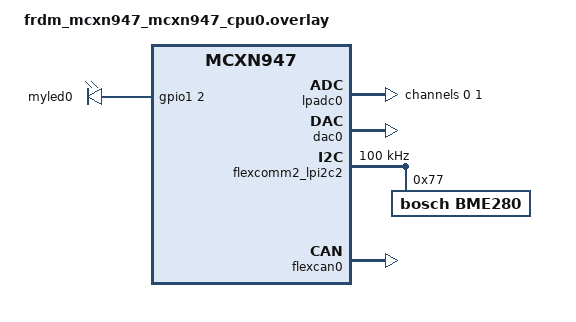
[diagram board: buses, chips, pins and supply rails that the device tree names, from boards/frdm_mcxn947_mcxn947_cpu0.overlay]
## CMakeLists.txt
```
# SPDX-License-Identifier: Apache-2.0

cmake_minimum_required(VERSION 3.20.0)

list(APPEND BOARD_ROOT ${CMAKE_CURRENT_SOURCE_DIR})
set(BOARD "frdm_mcxn947/mcxn947/cpu0")

set(VERSION_MAJOR "1")
set(VERSION_MINOR "0")
set(PATCHLEVEL "0")
set(VERSION_TWEAK "0")
set(EXTRAVERSION "00000000")

find_package(Git QUIET REQUIRED)

execute_process(
    COMMAND "${GIT_EXECUTABLE}" rev-parse --short HEAD
    WORKING_DIRECTORY "${CMAKE_SOURCE_DIR}"
    RESULT_VARIABLE res
    OUTPUT_VARIABLE EXTRAVERSION
    ERROR_QUIET
    OUTPUT_STRIP_TRAILING_WHITESPACE)

set_property(GLOBAL APPEND
    PROPERTY CMAKE_CONFIGURE_DEPENDS
    "${CMAKE_SOURCE_DIR}/.git/index")

set(BOARD_FLASH_RUNNER "probe-rs")
set(BOARD_DEBUG_RUNNER "probe-rs")

# utilize settings to autogenerate a header file to adjust the build inside the C code
#
configure_file (
   "${CMAKE_SOURCE_DIR}/src/VERSION.in"
   "${CMAKE_SOURCE_DIR}/VERSION"
   )

find_package(Zephyr REQUIRED HINTS $ENV{ZEPHYR_BASE})

project(oresat_template LANGUAGES C)

include_directories("${PROJECT_SOURCE_DIR}") # needed so c code can find this header

# (*) zephyr_include_directories(od)
zephyr_include_directories(objdict)

# (*)=disabled until oresat-configs supports code generation for Zephyr's canopennode
# (*) execute_process(COMMAND bash -c "oresat-configs canopennode od.yaml ../../common/od.yaml -d gen")

target_sources(app PRIVATE
  src/main.c
)

# Compile in various demos depending on Kconfig values.
target_sources_ifdef(CONFIG_BLINK_DEMO      app PRIVATE src/blink.c)
target_sources_ifdef(CONFIG_I2C_SENSOR_DEMO app PRIVATE src/i2c_sensor.c)
target_sources_ifdef(CONFIG_DAC_DEMO        app PRIVATE src/dac.c)
target_sources_ifdef(CONFIG_ADC_DEMO        app PRIVATE src/adc.c)
target_sources_ifdef(CONFIG_CAN_DEMO        app PRIVATE src/can.c)
target_sources_ifdef(CONFIG_GPIO_DEMO       app PRIVATE src/gpio.c)
target_sources_ifdef(CONFIG_CAN_DEMO        app PRIVATE objdict/CO_OD.c)
# (*) target_sources_ifdef(CONFIG_CAN_DEMO       app PRIVATE od/CO_OD.c)
```

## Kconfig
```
# SPDX-License-Identifier: Apache-2.0

menu "Zephyr"
source "Kconfig.zephyr"
endmenu

module = APP_TEMPLATE
module-str = APP TEMPLATE

config BOARD_OVERLAY_PRESENT
	bool
	default $(dt_nodelabel_exists,oresat_demo)

if BOARD_OVERLAY_PRESENT

	menu "Oresat demo options"

	config BLINK_DEMO
		bool "Blink an LED"
		default y
		help
		  Enable the thread which blinks an LED.

	config I2C_SENSOR_DEMO
		bool "Enable monitoring an I2C sensor"
		default y
		select I2C
		select SENSOR
		select SENSOR_ASYNC_API
		help
		  Enable reading from a Bosch Sensortec BME280.

	config DAC_DEMO
		bool "Enable generation of a sawtooth pattern."
		default y
		select DAC
		help
		  Enable a slowly repeating sawtooth from 0 to 3.3v.

	config CAN_DEMO
		bool "Enable sending CAN packets."
		default y
		select CAN
		select CANOPENNODE
		select USE_STM32_HAL_FLASH if SOC_STM32F091XC
		select USE_STM32_HAL_FLASH_EX if SOC_STM32F091XC
		select USE_STM32_HAL_CAN if SOC_STM32F091XC
		help
		  Enable CAN interface and send data from CO_OD.

	config GPIO_DEMO
		bool "Enable monitoring GPIOs."
		default y
		help
		  Enable logging of initial GPIO states, followed
		  by periodic logging of changes.

	config ADC_DEMO
		bool "Enable monitoring one or more ADC channels."
		default y
		select ADC
		select DMA
		select ADC_STM32 if SOC_STM32F091XC
		select ADC_STM32_DMA if SOC_STM32F091XC
		select DMA_STM32 if SOC_STM32F091XC
		help
		  Outputs the data scaled to mV.

	if ADC_DEMO

		config SEQUENCE_SAMPLES
			int "Number of samples to be made on the sequence for each channel."
			default 5

		config SEQUENCE_RESOLUTION
			int "Set the resolution of the sequence readings."
			default 12

		config SEQUENCE_32BITS_REGISTERS
			bool "ADC data sequences are on 32bits"
			default n

	endif  # ADC_DEMO

	if CAN_DEMO && !SOC_STM32F091XC && !ARCH_POSIX

		config MCUBOOT_ALLOWED
			bool "MCUboot allowed."
			default y
			select BOOTLOADER_MCUBOOT
			select MCUBOOT_GENERATE_UNSIGNED_IMAGE
			select FLASH
			select FLASH_MAP
			select STREAM_FLASH
			select IMG_MANAGER
			select MCUBOOT_GENERATE_CONFIRMED_IMAGE
			select CANOPENNODE_PROGRAM_DOWNLOAD
			help
			  Define helper symbol CONFIG_MCUBOOT_ALLOWED for all supported
			  architectures that have room for the required partitions in flash
			  and have those partitions defined in the device tree. This
			  eliminates the need for the user to either change prj.conf to
			  enable MCUBOOT or provide an EXTRA_CONF_FILE option to west that
			  names an overlay file.

	endif

	endmenu

endif # BOARD_OVERLAY_PRESENT
```

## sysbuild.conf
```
SB_CONFIG_BOOTLOADER_MCUBOOT=n
SB_CONFIG_BOOT_SIGNATURE_TYPE_NONE=y
```

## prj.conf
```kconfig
CONFIG_PRINTK=y
CONFIG_CONSOLE=y
CONFIG_SERIAL=y
CONFIG_UART_CONSOLE=y

CONFIG_PM=y
CONFIG_PM_DEVICE=y
CONFIG_PM_DEVICE_RUNTIME=y
CONFIG_PM_POLICY_CUSTOM=y
#CONFIG_PM_S2RAM=y

CONFIG_TICKLESS_KERNEL=y

CONFIG_COUNTER=y
CONFIG_COUNTER_MCUX_LPTMR_ALARM=y
CONFIG_PM_PREWAKEUP_CONV_MODE_CEIL=y

CONFIG_PM_DEVICE_SYSTEM_MANAGED=y
```

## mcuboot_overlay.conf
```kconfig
CONFIG_BOOTLOADER_MCUBOOT=y
CONFIG_MCUBOOT_GENERATE_UNSIGNED_IMAGE=y
# CONFIG_MCUBOOT_SIGNATURE_KEY_FILE=""
CONFIG_FLASH=y
CONFIG_FLASH_MAP=y
CONFIG_STREAM_FLASH=y
CONFIG_IMG_MANAGER=y
CONFIG_MCUBOOT_IMG_MANAGER=y
CONFIG_MCUBOOT_GENERATE_CONFIRMED_IMAGE=n
```

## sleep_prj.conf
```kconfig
CONFIG_PRINTK=y
CONFIG_CONSOLE=y
CONFIG_SERIAL=y
CONFIG_UART_CONSOLE=y

CONFIG_PM=y
CONFIG_PM_DEVICE=y
CONFIG_PM_DEVICE_RUNTIME=y

CONFIG_TICKLESS_KERNEL=y
```

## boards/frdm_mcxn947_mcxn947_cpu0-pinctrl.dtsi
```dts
&pinctrl {
	pinmux_flexcomm2_lpi2c: pinmux_flexcomm2_lpi2c {
		group0 {
			pinmux = <FC2_P0_PIO4_0>, // SDA  Header: J7  Pin: 8
    			     <FC2_P1_PIO4_1>; // SCL  Header: J7  Pin: 6
			slew-rate = "fast";
			drive-strength = "low";
			input-enable;
			bias-pull-up;
			drive-open-drain;
		};
	};

    pinmux_dac0: pinmux_dac0 {
        group0 {
            pinmux = <DAC0_OUT_PIO4_2>; // Header: J1  Pin: 4
            drive-strength = "low";
            slew-rate = "fast";
        };
    };

    pinmux_lpadc0: pinmux_lpadc0 {
        group0 {
            pinmux = <ADC0_A14_PIO0_22>, // Header: J4  Pin: 8
                     <ADC0_A15_PIO0_23>; // Header: J4  Pin: 12
            slew-rate = "fast";
            drive-strength = "low";
        };
    };

    pinmux_flexcan0: pinmux_flexcan0 {
        group0 {
            pinmux = <CAN0_TXD_PIO1_10>,
                     <CAN0_RXD_PIO1_11>;
            slew-rate = "fast";
            drive-strength = "low";
        };
    };
};
```

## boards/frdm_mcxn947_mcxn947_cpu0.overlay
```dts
#include <zephyr/dt-bindings/adc/adc.h>
#include <zephyr/dt-bindings/adc/mcux-lpadc.h>

#include "frdm_mcxn947_mcxn947_cpu0-pinctrl.dtsi"

/ {
	oresat_demo: oresat-demo-enabled {}; // Enable demos for supported boards

	zephyr,user {
		dac = <&dac0>;
		dac_channel_id = <0>;
		dac_resolution = <12>;
	};

	aliases {
		dac0 = &dac0;
		adc0 = &lpadc0;
		i2c0 = &flexcomm2_lpi2c2;
		led0 = &myled0;
		can0 = &flexcan0;
	};

	leds {
		compatible = "gpio-leds";
		myled0: led_0 {
			gpios = <&gpio1 2 GPIO_ACTIVE_HIGH>;
		};
	};
};

&lpadc0 {
	#address-cells = <1>;
	#size-cells = <0>;
	voltage-ref = <0x0>; // Use 3.3V reference
	pinctrl-0 = <&pinmux_lpadc0>;
	pinctrl-names = "default";

	lpadc0_0: channel@0 {
		reg = <0>;
		zephyr,gain = "ADC_GAIN_1";
		zephyr,reference = "ADC_REF_EXTERNAL0";
		zephyr,vref-mv = <3300>;
		zephyr,acquisition-time = <ADC_ACQ_TIME(ADC_ACQ_TIME_MICROSECONDS,2)>;
		zephyr,resolution = <12>;
		zephyr,oversampling = <5>;
		zephyr,input-positive = <MCUX_LPADC_CH14A>;
		/delete-property/ zephyr,differential;
	};
	lpadc0_1: channel@1 {
		reg = <1>;
		zephyr,gain = "ADC_GAIN_1";
		zephyr,reference = "ADC_REF_EXTERNAL0";
		zephyr,vref-mv = <3300>;
		zephyr,acquisition-time = <ADC_ACQ_TIME(ADC_ACQ_TIME_MICROSECONDS,2)>;
		zephyr,resolution = <12>;
		zephyr,oversampling = <5>;
		zephyr,input-positive = <MCUX_LPADC_CH15A>;
		/delete-property/ zephyr,differential;
	};
};

&dac0 {
	status = "okay";
	pinctrl-0 = <&pinmux_dac0>;
	pinctrl-names = "default";
};

&flexcomm2_lpi2c2 {
	status = "okay";
	pinctrl-0 = <&pinmux_flexcomm2_lpi2c>;
	pinctrl-names = "default";
	clock-frequency = <I2C_BITRATE_STANDARD>;

	bme280: bme280@77 {
		compatible = "bosch,bme280";
		reg = <0x77>;
		status = "okay";
	};
};

&flexcan0 {
	status = "okay";
	pinctrl-0 = <&pinmux_flexcan0>;
	pinctrl-names = "default";
};
```

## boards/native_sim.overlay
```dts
#include <zephyr/dt-bindings/adc/adc.h>

/ {
    oresat_demo: oresat-demo-enabled {}; // Enable demos for supported boards

    chosen {
        zephyr,canbus = &can0;
    };

    aliases {
        adc0 = &adc;
        /* can0 = &can; */
    };

    adc: adc {
        compatible = "zephyr,adc-emul";
        status = "okay";
        #address-cells = <1>;
        #size-cells = <0>;
        nchannels = <32>;
        ref-internal-mv = <1>;

        channel@0 {
            reg = <0>;
            zephyr,gain = "ADC_GAIN_1";
            zephyr,reference = "ADC_REF_INTERNAL";
            zephyr,vref-mv = <3300>;
            zephyr,acquisition-time = <ADC_ACQ_TIME(ADC_ACQ_TIME_MICROSECONDS,2)>;
            zephyr,resolution = <12>;
            zephyr,oversampling = <5>;
            zephyr,input-positive = <0>;
        };
    };

    can: can {
        compatible = "zephyr,native-linux-can";
        status = "okay";
        host-interface = "zcan0";
        bitrate = <1000>;
    };
};
```

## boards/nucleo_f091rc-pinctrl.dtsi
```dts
&pinctrl {
    i2c1_sda_pb9: i2c1_sda_pb9 {
        pinmux = <STM32_PINMUX('B', 9, AF1)>; // SDA  Arduino: D14  Pin: PB9
        slew-rate = "medium-speed";
        bias-pull-up;
        drive-open-drain;
    };

    i2c1_scl_pb8: i2c1_scl_pb8 {
        pinmux = <STM32_PINMUX('B', 8, AF1)>; // SCL  Arduino: D15  Pin: PB8
        slew-rate = "medium-speed";
        bias-pull-up;
        drive-open-drain;
    };

    dac1_out1_pa4: dac1_out1_pa4 {
        pinmux = <STM32_PINMUX('A', 4, ANALOG)>; // DAC_OUT1  Arduino: A2  Pin: PA4
    };

    adc1_in0_pa0: adc1_in0_pa0 {
        pinmux = <STM32_PINMUX('A', 0, ANALOG)>; // ADC1_IN0  Arduino: A0  Pin: PA0
    };

    adc1_in1_pa1: adc1_in1_pa1 {
        pinmux = <STM32_PINMUX('A', 1, ANALOG)>; // ADC1_IN1  Arduino: A1  Pin: PA1
    };
};
```

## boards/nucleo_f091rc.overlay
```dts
#include <zephyr/dt-bindings/adc/adc.h>
#include <zephyr/dt-bindings/pinctrl/stm32-pinctrl.h>
#include <zephyr/dt-bindings/dma/stm32_dma.h>

#include "nucleo_f091rc-pinctrl.dtsi"

/ {
	oresat_demo: oresat-demo-enabled {}; // Enable demos for supported boards

	zephyr,user {
		dac = <&dac1>;
		dac_channel_id = <1>;
		dac_resolution = <12>;
	};

	aliases {
		dac0 = &dac1;
		adc0 = &adc1;
		i2c0 = &i2c1;
		led0 = &myled0;
	};

	leds {
		compatible = "gpio-leds";
		myled0: led_0 {
			gpios = <&gpioa 5 GPIO_ACTIVE_HIGH>;
		};
	};
};

&dma1 {
	status = "okay";
};

&adc1 {
	#address-cells = <1>;
	#size-cells = <0>;
	pinctrl-0 = <&adc1_in0_pa0 &adc1_in1_pa1>;
	pinctrl-names = "default";
	dmas = <&dma1 1 (STM32_DMA_PERIPH_RX |
					STM32_DMA_PRIORITY_HIGH |
					STM32_DMA_PERIPH_16BITS |
					STM32_DMA_MEM_16BITS)>;
	dma-names = "rx";

	adc1_0: channel@0 {
		reg = <0>;
		zephyr,gain = "ADC_GAIN_1";
		zephyr,reference = "ADC_REF_INTERNAL";
		zephyr,vref-mv = <3300>;
		zephyr,acquisition-time = <ADC_ACQ_TIME(ADC_ACQ_TIME_TICKS, 240)>;
		zephyr,resolution = <12>;
		zephyr,oversampling = <5>;
		/delete-property/ zephyr,differential;
	};
	adc1_1: channel@1 {
		reg = <1>;
		zephyr,gain = "ADC_GAIN_1";
		zephyr,reference = "ADC_REF_INTERNAL";
		zephyr,vref-mv = <3300>;
		zephyr,acquisition-time = <ADC_ACQ_TIME(ADC_ACQ_TIME_TICKS, 240)>;
		zephyr,resolution = <12>;
		zephyr,oversampling = <5>;
		/delete-property/ zephyr,differential;
	};
};

&dac1 {
	status = "okay";
	pinctrl-0 = <&dac1_out1_pa4>;
	pinctrl-names = "default";
};

&i2c1 {
	status = "okay";
	pinctrl-0 = <&i2c1_scl_pb8 &i2c1_sda_pb9>;
	pinctrl-names = "default";
	clock-frequency = <I2C_BITRATE_STANDARD>;

	bme280: bme280@77 {
		compatible = "bosch,bme280";
		reg = <0x77>;
		status = "okay";
	};
};
```

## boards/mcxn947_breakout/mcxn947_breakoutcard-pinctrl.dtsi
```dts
/*
 * Copyright 2024 NXP
 * SPDX-License-Identifier: Apache-2.0
 */

#include <nxp/mcx/MCXN947VNL-pinctrl.h>

&pinctrl {
	pinmux_flexcomm0_lpi2c: pinmux_flexcomm0_lpi2c {
		group0 {
			pinmux = <FC0_P0_PIO0_16>,
				<FC0_P1_PIO0_17>;
			slew-rate = "fast";
			drive-strength = "low";
			input-enable;
			bias-pull-up;
			drive-open-drain;
		};
	};

	pinmux_flexcomm3_lpspi: pinmux_flexcomm3_lpspi {
		group0 {
			pinmux = <FC3_P0_PIO1_0>,
				<FC3_P1_PIO1_1>,
				<FC3_P2_PIO1_2>,
				<FC3_P3_PIO1_3>;
			slew-rate = "fast";
			drive-strength = "low";
			input-enable;
		};
	};

	pinmux_flexcomm2_lpi2c: pinmux_flexcomm2_lpi2c {
		group0 {
			pinmux = <FC2_P0_PIO4_0>,
				<FC2_P1_PIO4_1>;
			slew-rate = "fast";
			drive-strength = "low";
			input-enable;
			bias-pull-up;
			drive-open-drain;
		};
	};

	pinmux_flexcomm2_lpuart: pinmux_flexcomm2_lpuart {
		group0 {
			pinmux = <FC2_P2_PIO4_2>,
				<FC2_P3_PIO4_3>;
			slew-rate = "fast";
			drive-strength = "low";
			input-enable;
		};
	};

	pinmux_flexcomm4_lpuart: pinmux_flexcomm4_lpuart {
		group0 {
			pinmux = <FC4_P0_PIO1_8>,
				<FC4_P1_PIO1_9>;
			slew-rate = "fast";
			drive-strength = "low";
			input-enable;
		};
	};

	pinmux_flexspi: pinmux_flexspi {
		group0 {
			pinmux = <FLEXSPI0_A_SS0_b_PIO3_0>,
					<FLEXSPI0_A_SCLK_PIO3_7>,
					<FLEXSPI0_A_DQS_PIO3_6>,
					<FLEXSPI0_A_DATA0_PIO3_8>,
					<FLEXSPI0_A_DATA1_PIO3_9>;
			input-enable;
			slew-rate = "fast";
			drive-strength = "low";
		};
		group1 {
			pinmux = <FLEXSPI0_A_DATA2_PIO3_10>,
					<FLEXSPI0_A_DATA3_PIO3_11>;
			input-enable;
			slew-rate = "fast";
			drive-strength = "low";
			bias-pull-up;
		};
	};

	pinmux_dac0: pinmux_dac0 {
		group0 {
			pinmux = <DAC0_OUT_PIO4_2>;
			drive-strength = "low";
			slew-rate = "fast";
		};
	};

	pinmux_flexpwm1_pwm0: pinmux_flexpwm1_pwm0 {
		group0 {
			pinmux = <PWM1_A0_PIO2_6>,
				<PWM1_B0_PIO2_7>;
			slew-rate = "fast";
			drive-strength = "low";
		};
	};

	pinmux_flexpwm1_pwm1: pinmux_flexpwm1_pwm1 {
		group0 {
			pinmux = <PWM1_A1_PIO2_4>,
				<PWM1_B1_PIO2_5>;
			slew-rate = "fast";
			drive-strength = "low";
		};
	};

	pinmux_flexpwm1_pwm2: pinmux_flexpwm1_pwm2 {
		group0 {
			pinmux = <PWM1_A2_PIO2_2>,
				<PWM1_B2_PIO2_3>;
			slew-rate = "fast";
			drive-strength = "low";
		};
	};

	pinmux_usdhc0: pinmux_usdhc0 {
		group0 {
			pinmux = <SDHC0_CMD_PIO2_5>,
				   <SDHC0_D0_PIO2_3>,
				   <SDHC0_D1_PIO2_2>,
				   <SDHC0_D2_PIO2_7>,
				   <SDHC0_D3_PIO2_6>;
			slew-rate = "fast";
			drive-strength = "low";
			bias-pull-up;
			input-enable;
		};
		group1 {
			pinmux = <SDHC0_CLK_PIO2_4>;
			slew-rate = "fast";
			drive-strength = "low";
			input-enable;
		};
	};

	pinmux_lpadc0: pinmux_lpadc0 {
		group0 {
			pinmux = <ADC0_A1_PIO4_15>,
					 <ADC0_A2_PIO4_23>;
			slew-rate = "fast";
			drive-strength = "low";
		};
	};

	pinmux_lpcmp0: pinmux_lpcmp0 {
		group0 {
			pinmux = <CMP0_IN0_PIO1_0>;
			drive-strength = "low";
			slew-rate = "fast";
			bias-pull-up;
		};
	};

	pinmux_flexcan0: pinmux_flexcan0 {
		group0 {
			pinmux = <CAN0_TXD_PIO1_10>,
				<CAN0_RXD_PIO1_11>;
			slew-rate = "fast";
			drive-strength = "low";
			input-enable;
		};
	};

	pinmux_sctimer: pinmux_sctimer {
		group0 {
			pinmux = <SCT0_OUT0_PIO2_2>;
			slew-rate = "fast";
			drive-strength = "low";
			input-enable;
		};
	};
};
```

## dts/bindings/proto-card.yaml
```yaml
# Oresat proto card

description: Oresat proto card

compatible: "proto-card"

properties:
  tp84-p0-3-gpios:
    type: phandle-array
    required: true
    description: GPIO input or output.

  tp84-p0-3-gpios:
    type: phandle-array
    required: true
    description: GPIO input or output.

  tp85-p0-4-gpios:
    type: phandle-array
    required: true
    description: GPIO input or output.

  tp86-p0-5-gpios:
    type: phandle-array
    required: true
    description: GPIO input or output.

  tp78-p0-18-gpios:
    type: phandle-array
    required: true
    description: GPIO input or output.

  tp79-p0-19-gpios:
    type: phandle-array
    required: true
    description: GPIO input or output.

  tp80-p0-20-gpios:
    type: phandle-array
    required: true
    description: GPIO input or output.

  tp81-p0-21-gpios:
    type: phandle-array
    required: true
    description: GPIO input or output.

  tp82-p0-22-gpios:
    type: phandle-array
    required: true
    description: GPIO input or output.

  tp83-p0-23-gpios:
    type: phandle-array
    required: true
    description: GPIO input or output.

  tp68-p1-0-gpios:
    type: phandle-array
    required: true
    description: GPIO input or output.

  tp69-p1-1-gpios:
    type: phandle-array
    required: true
    description: GPIO input or output.

  tp70-p1-2-gpios:
    type: phandle-array
    required: true
    description: GPIO input or output.

  tp71-p1-3-gpios:
    type: phandle-array
    required: true
    description: GPIO input or output.

  tp72-p1-4-gpios:
    type: phandle-array
    required: true
    description: GPIO input or output.

  tp73-p1-5-gpios:
    type: phandle-array
    required: true
    description: GPIO input or output.

  tp74-p1-6-gpios:
    type: phandle-array
    required: true
    description: GPIO input or output.

  tp75-p1-7-gpios:
    type: phandle-array
    required: true
    description: GPIO input or output.

  tp5-p1-12-gpios:
    type: phandle-array
    required: true
    description: GPIO input or output.

  tp7-p1-14-gpios:
    type: phandle-array
    required: true
    description: GPIO input or output.

  tp8-p1-15-gpios:
    type: phandle-array
    required: true
    description: GPIO input or output.

  tp9-p2-0-gpios:
    type: phandle-array
    required: true
    description: GPIO input or output.

  tp10-p2-1-gpios:
    type: phandle-array
    required: true
    description: GPIO input or output.

  tp52-p3-1-gpios:
    type: phandle-array
    required: true
    description: GPIO input or output.

  tp60-p3-12-gpios:
    type: phandle-array
    required: true
    description: GPIO input or output.

  tp59-p3-13-gpios:
    type: phandle-array
    required: true
    description: GPIO input or output.

  tp58-p3-14-gpios:
    type: phandle-array
    required: true
    description: GPIO input or output.

  tp57-p3-15-gpios:
    type: phandle-array
    required: true
    description: GPIO input or output.

  tp56-p3-16-gpios:
    type: phandle-array
    required: true
    description: GPIO input or output.

  tp55-p3-17-gpios:
    type: phandle-array
    required: true
    description: GPIO input or output.

  tp62-p3-20-gpios:
    type: phandle-array
    required: true
    description: GPIO input or output.

  tp63-p3-21-gpios:
    type: phandle-array
    required: true
    description: GPIO input or output.

  tp29-p4-1-gpios:
    type: phandle-array
    required: true
    description: GPIO input or output.

  tp27-p4-3-gpios:
    type: phandle-array
    required: true
    description: GPIO input or output.

  tp26-p4-4-gpios:
    type: phandle-array
    required: true
    description: GPIO input or output.

  tp25-p4-5-gpios:
    type: phandle-array
    required: true
    description: GPIO input or output.

  tp22-p4-6-gpios:
    type: phandle-array
    required: true
    description: GPIO input or output.

  tp20-p4-7-gpios:
    type: phandle-array
    required: true
    description: GPIO input or output.

  tp41-p4-19-gpios:
    type: phandle-array
    required: true
    description: GPIO input or output.

  tp64-p5-0-gpios:
    type: phandle-array
    required: true
    description: GPIO input or output.

  tp65-p5-1-gpios:
    type: phandle-array
    required: true
    description: GPIO input or output.

  tp66-p5-2-gpios:
    type: phandle-array
    required: true
    description: GPIO input or output.

  tp67-p5-3-gpios:
    type: phandle-array
    required: true
    description: GPIO input or output.
```

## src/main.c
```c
#include "zephyr/pm/state.h"
#include <zephyr/kernel.h>
#include <zephyr/sys/printk.h>
#include <zephyr/pm/policy.h>
#include <zephyr/pm/pm.h>

#define SLEEP_TIME_MS 5000

 //This function is called by Zephyr's PM subsystem whenever the CPU becomes idle.
 
 //PM Policy callback
const struct pm_state_info *pm_policy_next_state(uint8_t cpu, int32_t ticks)
{
    ARG_UNUSED(ticks);   //Prevents unused variable warnings 

    printk("\n>>> pm_policy_next_state() CALLED <<<\n");

    const struct pm_state_info *cpu_states;      // Pointer to available PM states
    uint8_t num_states;                          // Number of available states

    num_states = pm_state_cpu_get_all(cpu, &cpu_states);   // Get all supported power states for this CPU

    printk("Number of CPU power states: %d\n", num_states);

    if (num_states == 0) {
        printk("ERROR: No power states found!\n");
        return NULL;   //No state available
    }

// Loop through all available states
    for (int i = 0; i < num_states; i++) {

        printk("Checking state %d (enum value = %d)\n",
               i,
               cpu_states[i].state);

        if (cpu_states[i].state == PM_STATE_SUSPEND_TO_IDLE) {

            printk("Slecting PM_STATE_SUSPEND_TO_IDLE");

            return &cpu_states[i];
        }

        //if (cpu_states[i].state == PM_STATE_RUNTIME_IDLE) {

        //    printk("Selecting PM_STATE_RUNTIME_IDLE\n");

        //    return &cpu_states[i];     //tells zephyr to enter this state
        //}
    }

    printk("ERROR: PM_STATE_RUNTIME_IDLE not found!\n");

    return NULL;   //No matching state found
}

int main(void)
{
    printk("\n");
    printk("=====================================\n");
    printk(" MCXN947 Sleep Mode Test\n");
    printk("=====================================\n");

    printk("\nCPU ACTIVE\n");                   //CPU running normally
    printk("Preparing to enter Sleep...\n");

    k_sleep(K_MSEC(SLEEP_TIME_MS));   // Allows idle mode

    printk("CPU AWAKE\n");    //Runs after sleep completes

    while (1) {
        printk("done sleeping");
    }

    return 0;
}
```

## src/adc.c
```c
/**
 * adc.c
 *
 * Original code came from zephyr/samples/driver/adc_sequence.
 *
 * Modified slightly to run as a thread and use logging.
 */

#ifdef CONFIG_ADC_EMUL
#include <zephyr/drivers/adc/adc_emul.h>
#include <math.h>
#endif /* ifdef CONFIG_ADC_EMUL */

#include <stdio.h>
#include <zephyr/kernel.h>
#include <zephyr/sys/printk.h>
#include <zephyr/sys/__assert.h>

#include <zephyr/device.h>
#include <zephyr/devicetree.h>
#include <zephyr/dsp/print_format.h>
#include <zephyr/drivers/adc.h>
#include <zephyr/logging/log.h>

LOG_MODULE_REGISTER(oresat_adc_demo, LOG_LEVEL_DBG);

/* size of stack area used by each thread */
#define STACKSIZE 1024

/* scheduling priority used by each thread */
#define PRIORITY 7

/* 1000 msec = 1 sec */
#define ADC_SLEEP_TIME_MS 100 /* Use 5 to generate more data to graph samples that follow the DAC output */

/* ADC node from the devicetree. */
#define ADC_NODE DT_ALIAS(adc0)

/* Auxiliary macro to obtain channel vref, if available. */
#define CHANNEL_VREF(node_id) DT_PROP_OR(node_id, zephyr_vref_mv, 0)

/* Data of ADC device specified in devicetree. */
static const struct device *adc = DEVICE_DT_GET(ADC_NODE);

/* Data array of ADC channels for the specified ADC. */
static const struct adc_channel_cfg channel_cfgs[] = {
	DT_FOREACH_CHILD_SEP(ADC_NODE, ADC_CHANNEL_CFG_DT, (,))};

/* Data array of ADC channel voltage references. */
static uint32_t vrefs_mv[] = {DT_FOREACH_CHILD_SEP(ADC_NODE, CHANNEL_VREF, (,))};

/* Get the number of channels defined on the DTS. */
#define CHANNEL_COUNT ARRAY_SIZE(channel_cfgs)

static int handle_adc(void)
{
	int err;
#ifdef CONFIG_SEQUENCE_32BITS_REGISTERS
	uint32_t channel_reading[CONFIG_SEQUENCE_SAMPLES][CHANNEL_COUNT];
#else
	uint16_t channel_reading[CONFIG_SEQUENCE_SAMPLES][CHANNEL_COUNT];
#endif

	/* Options for the sequence sampling. */
	const struct adc_sequence_options options = {
		.extra_samplings = CONFIG_SEQUENCE_SAMPLES - 1,
		.interval_us = 0,
	};

	/* Configure the sampling sequence to be made. */
	struct adc_sequence sequence = {
		.buffer = channel_reading,
		/* buffer size in bytes, not number of samples */
		.buffer_size = sizeof(channel_reading),
		.resolution = CONFIG_SEQUENCE_RESOLUTION,
		.options = &options,
	};

	LOG_INF("Starting ADC demo");

	if (!device_is_ready(adc)) {
		LOG_ERR("ADC controller device %s not ready", adc->name);
		return 0;
	}

	LOG_INF("Channels: %d, sequence samples: %d, resolution: %d",
		   CHANNEL_COUNT, CONFIG_SEQUENCE_SAMPLES, CONFIG_SEQUENCE_RESOLUTION);

	/* Configure channels individually prior to sampling. */
	for (size_t i = 0U; i < CHANNEL_COUNT; i++) {
		sequence.channels |= BIT(channel_cfgs[i].channel_id);
		err = adc_channel_setup(adc, &channel_cfgs[i]);
		if (err < 0) {
			LOG_ERR("Could not setup channel #%d (%d)\n", i, err);
			return 0;
		}
		if ((vrefs_mv[i] == 0) && (channel_cfgs[i].reference == ADC_REF_INTERNAL)) {
			vrefs_mv[i] = adc_ref_internal(adc);
		}
		#ifdef CONFIG_ADC_CONFIGURABLE_INPUTS
		LOG_INF("Channel: %u, vref_mv: %u, gain: %u, acq time: %u, diff: %u, inp_pos: %u, inp_neg: %u",
				channel_cfgs[i].channel_id, vrefs_mv[i], channel_cfgs[i].gain, channel_cfgs[i].acquisition_time,
				channel_cfgs[i].differential, channel_cfgs[i].input_positive, channel_cfgs[i].input_negative);
		#else
		LOG_INF("Channel: %u, vref_mv: %u, gain: %u, acq time: %u, diff: %u",
				channel_cfgs[i].channel_id, vrefs_mv[i], channel_cfgs[i].gain, channel_cfgs[i].acquisition_time,
				channel_cfgs[i].differential);
		#endif
	}

#ifdef CONFIG_ADC_EMUL
	uint32_t adc_val = 0;
#endif /* ifdef CONFIG_ADC_EMUL */

	while (1) {
		k_msleep(ADC_SLEEP_TIME_MS);

#ifdef CONFIG_ADC_EMUL
		uint32_t adc_raw = (uint32_t)((sin(adc_val) + 1) * 1000);
		adc_emul_const_raw_value_set(adc, 0, adc_raw);
		adc_val++;
#endif /* ifdef CONFIG_ADC_EMUL */

		err = adc_read(adc, &sequence);
		if (err < 0) {
			LOG_ERR("Could not read (%d)", err);
			continue;
		}

		for (size_t channel_index = 0U; channel_index < CHANNEL_COUNT; channel_index++) {
			int32_t raw;
			int32_t val_mv;

			printk("Channel %" PRId32 ":", channel_index);

			for (size_t sample_index = 0U; sample_index < CONFIG_SEQUENCE_SAMPLES;
			     sample_index++) {

				raw = channel_reading[sample_index][channel_index];
				val_mv = raw;

				err = adc_raw_to_millivolts(vrefs_mv[channel_index],
							    channel_cfgs[channel_index].gain,
							    CONFIG_SEQUENCE_RESOLUTION, &val_mv);

				/* conversion to mV may not be supported, skip if not */
				if ((err < 0) || vrefs_mv[channel_index] == 0) {
					printk("% 4" PRId32 ",", raw);
				} else {
					printk("% 4" PRId32 ",", val_mv);
				}
			}
			printk("\n");
		}
	}

	return 0;
}

K_THREAD_DEFINE(adc_id, STACKSIZE, handle_adc, NULL, NULL, NULL, PRIORITY, 0, 0);
```

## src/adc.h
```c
#if !defined(_ADC_H_)
#define _ADC_H_

int get_num_adc_channels(void);

int init_adc(void);

int acquire_adc_readings(void);

int read_adc(unsigned int log_adc_num, int32_t *val_mv, uint32_t *val_raw);

#endif
```

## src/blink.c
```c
/**
 * blink.c
 *
 * Code came from https://github.com/Blen-E/pracblink, which
 * originally from zephyr/samples/basic/blinky.
 *
 * Modified slightly to run as a thread and use logging.
 */
#include <stdio.h>
#include <zephyr/kernel.h>
#include <zephyr/drivers/gpio.h>
#include <zephyr/sys/printk.h> 
#include <zephyr/sys/__assert.h>

#include <zephyr/device.h>
#include <zephyr/devicetree.h>
#include <zephyr/logging/log.h>

LOG_MODULE_REGISTER(oresat_blink_demo, LOG_LEVEL_INF);

/* size of stack area used by each thread */
#define STACKSIZE 1024

/* scheduling priority used by each thread */
#define PRIORITY 7

/* 1000 msec = 1 sec */
#define LED_SLEEP_TIME_MS   1000

/* The devicetree node identifier for the "led0" alias. */
#define LED0_NODE DT_ALIAS(led0)

extern const k_tid_t blink_id;

static int handle_blink(void *p1, void *p2, void *p3)
{
	int ret;
	const struct gpio_dt_spec led = GPIO_DT_SPEC_GET(LED0_NODE, gpios);

	k_thread_name_set(blink_id, "blink_thread");
	LOG_INF("Starting blink demo");

	/* Can we use the LED? */
	if (!device_is_ready(led.port)) {
		LOG_ERR("LED device is not ready");
		return -1;
	}

	/* Set it up */
	ret = gpio_pin_configure_dt(&led, GPIO_OUTPUT_ACTIVE);
	if (ret < 0) {
		LOG_ERR("Could not configure the LED GPIO pin: %d", ret);
		return ret;
	}

	/* Thread loop */
	while (1) {
		gpio_pin_toggle_dt(&led);
		LOG_DBG("The light is blinking!");
		k_msleep(LED_SLEEP_TIME_MS);
	}
	return 0;
}

K_THREAD_DEFINE(blink_id, STACKSIZE, handle_blink, NULL, NULL, NULL, PRIORITY, 0, 0);
```

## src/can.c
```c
#include <zephyr/kernel.h>
#include <zephyr/device.h>
#include <zephyr/sys/reboot.h>
#include <zephyr/logging/log.h>
#include <zephyr/sys/printk.h>
#include <zephyr/drivers/gpio.h>
#include <zephyr/dfu/mcuboot.h>
#include <canopennode.h>
#include <CO_OD.h>
#include <board_sensors.h>
#include <oresat.h>

LOG_MODULE_REGISTER(can_thread, LOG_LEVEL_DBG);

#define CAN_INTERFACE (DEVICE_DT_GET(DT_CHOSEN(zephyr_canbus)))
#define CAN_BITRATE (DT_PROP_OR(DT_CHOSEN(zephyr_canbus), bitrate, \
					 DT_PROP_OR(DT_CHOSEN(zephyr_canbus), bus_speed, \
								CONFIG_CAN_DEFAULT_BITRATE) / 1000))

#define CAN_THREAD_STACK_SIZE 2048
#define CAN_THREAD_PRIORITY 0
extern const k_tid_t can_id;

static bool run_self_tests(void)
{
	LOG_INF("Running system self-tests...");

	// Placeholder for board/app-specific checks
	bool tests_passed = true;

	return tests_passed;
}

static void handle_can(void *p1, void *p2, void *p3)
{
	int err;
	uint16_t timeout;
	uint16_t wr_timeout_count;
	uint32_t elapsed = 0U;
	int64_t timestamp;
	CO_NMT_reset_cmd_t reset = CO_RESET_NOT;
	struct canopen_context can = {.dev = CAN_INTERFACE};
	uint8_t node_id = oresat_get_node_id();

	k_thread_name_set(can_id, "can_thread");

	LOG_INF("Starting CAN thread");

	// Confirm a newly booted MCUboot image if self-tests pass
	if (!IS_ENABLED(CONFIG_BOOTLOADER_MCUBOOT)) {
		/* do nothing */
	} else if (!boot_is_img_confirmed()) {
		LOG_INF("New firmware detected. Pending confirmation.");

		if (run_self_tests()) {
			LOG_INF("Self-tests passed. Confirming image.");
			int rc = boot_write_img_confirmed();
			if (rc < 0) {
				LOG_ERR("Failed to confirm MCUboot image: %d", rc);
			}
		} else {
			LOG_ERR("Self-tests failed. Rebooting to revert firmware...");
			k_msleep(500); // Let logs flush
			sys_reboot(SYS_REBOOT_COLD);
		}
	} else {
		LOG_INF("Firmware already confirmed.");
	}

	oresat_fix_pdo_cob_ids(node_id);

	LOG_DBG("Opening CAN device");
	if (!device_is_ready(can.dev)) {
		LOG_ERR("CAN interface is not ready");
		k_msleep(1000);
		__ASSERT(false, "Fatal error");
	}

	LOG_INF("Starting CANopenNode (node_id=%u, bitrate=%u kbps)",
			(unsigned)node_id, (unsigned)CAN_BITRATE);

	while (reset != CO_RESET_APP) {
		elapsed = 0U;
		wr_timeout_count = 0U;

		err = CO_init(&can, node_id, CAN_BITRATE);
		if (err != CO_ERROR_NO) {
			LOG_ERR("CO_init failed (err = %d)", err);
			k_msleep(1000);
			__ASSERT(false, "Fatal error");
		}

		if (IS_ENABLED(CONFIG_BOOTLOADER_MCUBOOT)) {
			canopen_program_download_attach(CO->NMT, CO->SDO[0], CO->em);
		}
		CO_CANsetNormalMode(CO->CANmodule[0]);

		LOG_INF("Template app running. Waiting for CANopen requests...");

		while (true) {
			bool_t syncWas = false;

			timeout = 1U;
			timestamp = k_uptime_get();

			if (CO_isError(CO->em, CO_EM_CAN_TX_OVERFLOW)) {
				CO_errorReset(CO->em, CO_EM_CAN_TX_OVERFLOW, 111);
			}

			if (wr_timeout_count++ >= 1000U) {
				wr_timeout_count = 0U;

				CO_LOCK_OD();
				CO_OD_RAM.pack_1.cycles++;
				CO_OD_RAM.pack_1.current = 100;
				CO_OD_RAM.pack_1.full_capacity = 1000;
				CO_OD_RAM.pack_1.status = 13;
				CO_OD_RAM.pack_1.temperature = 21;
				CO_OD_RAM.pack_1.vbatt = 79;
				CO_OD_RAM.pack_2.cycles++;
				CO_OD_RAM.pack_2.current = 200;
				CO_OD_RAM.pack_2.full_capacity = 1500;
				CO_OD_RAM.pack_2.status = 17;
				CO_OD_RAM.pack_2.temperature = 23;
				CO_OD_RAM.pack_2.vbatt = 84;
				CO_UNLOCK_OD();

			}

			reset = CO_process(CO, (uint16_t)elapsed, &timeout);
			if (reset != CO_RESET_NOT) {
				break;
			}

			if (timeout > 0) {
				/* Read inputs */
				CO_process_RPDO(CO, syncWas);

				/* Write outputs */
				CO_process_TPDO(CO, syncWas,  elapsed * 1000U);

				k_sleep(K_MSEC(timeout));
				elapsed = (uint32_t)k_uptime_delta(&timestamp);
			} else {
				elapsed = 0U;
			}

			if (reset == CO_RESET_COMM) {
				LOG_INF("Resetting communication");
			}
		}
	}

	CO_delete(&can);
	sys_reboot(SYS_REBOOT_COLD);
}

K_THREAD_DEFINE(can_id, CAN_THREAD_STACK_SIZE, handle_can, NULL, NULL, NULL, CAN_THREAD_PRIORITY, 0, 0);
```

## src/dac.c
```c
/**
 * dac.c
 *
 * Original code came from zephyr/samples/driver/dac.
 *
 * Modified slightly to run as a thread and use logging.
 */
#include <stdio.h>
#include <zephyr/kernel.h>
#include <zephyr/sys/printk.h> 
#include <zephyr/sys/__assert.h>

#include <zephyr/device.h>
#include <zephyr/devicetree.h>
#include <zephyr/drivers/sensor.h>
#include <zephyr/drivers/sensor_data_types.h>
#include <zephyr/rtio/rtio.h>
#include <zephyr/dsp/print_format.h>
#include <zephyr/drivers/dac.h>
#include <zephyr/drivers/adc.h>
#include <zephyr/logging/log.h>

LOG_MODULE_REGISTER(oresat_dac_demo, LOG_LEVEL_DBG);

/* size of stack area used by each thread */
#define STACKSIZE 2048

/* scheduling priority used by each thread */
#define PRIORITY_DAC 6

#define ZEPHYR_USER_NODE DT_PATH(zephyr_user)

#if (DT_NODE_HAS_PROP(ZEPHYR_USER_NODE, dac) && \
	DT_NODE_HAS_PROP(ZEPHYR_USER_NODE, dac_channel_id) && \
	DT_NODE_HAS_PROP(ZEPHYR_USER_NODE, dac_resolution))
#define DAC_NODE DT_PHANDLE(ZEPHYR_USER_NODE, dac)
#define DAC_CHANNEL_ID DT_PROP(ZEPHYR_USER_NODE, dac_channel_id)
#define DAC_RESOLUTION DT_PROP(ZEPHYR_USER_NODE, dac_resolution)
#else
#error "Unsupported board: see README and check /zephyr,user node"
#define DAC_NODE DT_INVALID_NODE
#define DAC_CHANNEL_ID 0
#define DAC_RESOLUTION 0
#endif

extern const k_tid_t dac_id;

static int handle_dac(void *p1, void *p2, void *p3)
{
	int ret;
	const struct device *const dac_dev = DEVICE_DT_GET(DAC_NODE);
	const struct dac_channel_cfg dac_ch_cfg = {
		.channel_id  = DAC_CHANNEL_ID,
		.resolution  = DAC_RESOLUTION,
	#if defined(CONFIG_DAC_BUFFER_NOT_SUPPORT)
		.buffered = false,
	#else
		.buffered = true,
	#endif /* CONFIG_DAC_BUFFER_NOT_SUPPORT */
	};

	k_thread_name_set(dac_id, "dac_thread");
	LOG_INF("Starting DAC demo");

	/* Can we use the DAC? */
	if (!device_is_ready(dac_dev)) {
		LOG_ERR("DAC device %s is not ready", dac_dev->name);
		return -1;
	}

	/* Set it up */
	ret = dac_channel_setup(dac_dev, &dac_ch_cfg);
	if (ret != 0) {
		LOG_ERR("Setting up of DAC channel failed with code %d", ret);
		return ret;
	}

	/* Number of valid DAC values, e.g. 4096 for 12-bit DAC */
	const int dac_values = 1U << DAC_RESOLUTION;
	/*
	 * 100 usec sleep leads to about 0.4 sec signal period for 12-bit
	 * DACs. For DACs with lower resolution, sleep time needs to
	 * be increased.
	 */
	const int sleep_time = ((4096 / dac_values) > 0 ? (4096 / dac_values) : 1) * 1000;

	LOG_DBG("Generating sawtooth signal at DAC channel %d.", DAC_CHANNEL_ID);
	LOG_DBG("Number of DAC samples per cycle: %d, sleep time per sample (us): %d",
		   dac_values, sleep_time);
	int cycle = 0;

	while (1) {
		for (int i = 0; i < dac_values; i++) {
			ret = dac_write_value(dac_dev, DAC_CHANNEL_ID, i);
			if (ret != 0) {
				LOG_ERR("dac_write_value() failed with code %d", ret);
				return ret;
			}
			k_sleep(K_USEC(sleep_time));
		}
		LOG_INF("Cycle %u", ++cycle);
	}
	return 0;
}

K_THREAD_DEFINE(dac_id, STACKSIZE, handle_dac, NULL, NULL, NULL, PRIORITY_DAC, 0, 0);
```

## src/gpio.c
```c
/**
 * gpio.c
 *
 * Show how to access GPIOs on a board.
 *
 */
#include <stdio.h>
#include <zephyr/kernel.h>
#include <zephyr/sys/printk.h>
#include <zephyr/sys/__assert.h>

#include <zephyr/device.h>
#include <zephyr/devicetree.h>
#include <zephyr/dsp/print_format.h>
#include <zephyr/logging/log.h>
#include <zephyr/drivers/gpio.h>

LOG_MODULE_REGISTER(oresat_gpio_demo, LOG_LEVEL_INF);

/* size of stack area used by each thread */
#define STACKSIZE 1024

/* scheduling priority used by each thread */
#define PRIORITY_GPIO 6

#define GPIO_SLEEP_TIME_MS 5000

extern const k_tid_t gpio_id;

/**************************************************/
#if defined(CONFIG_BOARD_MCXN947_PROTOCARD)
#define BP_NODE DT_NODELABEL(protogpios)

/**
 * Use X Macros to define board-specific GPIO definitions
 * (GPIO_DEFS).
 *
 * Define the raw data that lists test point number, port
 * number, and bit number in the port. For example, the first
 * line corresponds to TP84, which is connected to P0_3.
 *
 * Use that data in the next section to generate an enumeration
 * of all the test point names (e.g, TP84) and an array of
 * structures for storing the device tree gpio access objects as
 * well as ints for the three columns.
 *
 * This array of structs can be indexed with the enumeration
 * values to provide easy access to any specific test point
 * GPIO.
 **/
#define GPIO_DEFS \
	X(84, 0,  3) \
	X(85, 0,  4) \
	X(86, 0,  5) \
	X(78, 0, 18) \
	X(79, 0, 19) \
	X(80, 0, 20) \
	X(81, 0, 21) \
	X(82, 0, 22) \
	X(83, 0, 23) \
	X(68, 1,  0) \
	X(69, 1,  1) \
	X(70, 1,  2) \
	X(71, 1,  3) \
	X(72, 1,  4) \
	X(73, 1,  5) \
	X(74, 1,  6) \
	X(75, 1,  7) \
	X( 5, 1, 12) \
	X( 7, 1, 14) \
	X( 8, 1, 15) \
	X( 9, 2,  0) \
	X(10, 2,  1) \
	X(52, 3,  1) \
	X(60, 3, 12) \
	X(59, 3, 13) \
	X(58, 3, 14) \
	X(57, 3, 15) \
	X(56, 3, 16) \
	X(55, 3, 17) \
	X(62, 3, 20) \
	X(63, 3, 21) \
	X(29, 4,  1) \
	X(27, 4,  3) \
	X(26, 4,  4) \
	X(25, 4,  5) \
	X(22, 4,  6) \
	X(20, 4,  7) \
	X(41, 4, 19) \
	X(64, 5,  0) \
	X(65, 5,  1) \
	X(66, 5,  2) \
	X(67, 5,  3)

/**
 * Instantiate the X macro to use the ## token pasting operator
 * to generate enums for each test point name.
 *
 * Use this X macro by invoking GPIO_DEFS. This automatically
 * fills in a comma-separated list of enumeration names.
 *
 * We also automatically get a count of the number of test
 * points defined as NUM_GPIO_TPS.
 *
 * After this X macro is used, undefine it so another X macro
 * can be created to use the same raw data above.
 *
 * The resulting enums will be named, for example:
 *   TP84 for port 0 bit 3
 *   TP85 for port 0 bit 4
 * You can then use these names in your custom source code.
 *
 **/
#define X(tpnum, port, bit) TP ## tpnum,
typedef enum {
	GPIO_DEFS
	NUM_GPIO_TPS
} GPIO_TPS;
#undef X

/**
 * Define a structure to store the gpio_dt_spec, and integers to
 * store the tpnum, port, and bit.
 */
typedef struct gpio_tp {
	const struct gpio_dt_spec dt;
	int tpnum;
	int port;
	int bit;
} gpio_tp;

/**
 * Instantiate a new X macro to generate build-time
 * initialization data for each GPIO. It must be done at
 * build-time due to the way that the Zephyr device tree access
 * from C is done using macros.
 *
 * Use the X macro to generate initialization data for an array
 * of these structures, by invoking GPIO_DEFS again.
 *
 * As recommended, undefine X so it could be redefined later.
 *
 * An example initialization entry for the array is:
 *
 *   {GPIO_DT_SPEC_GET(BP_NODE, tp84_p0_3_gpios), 84, 0, 3},
 *
 * You can then access a specific gpio_tp structure in the
 * gpio_tp_array by enum name, such as:
 *
 *   gpio_tp *my_new_led = &gpio_tp_array[TP84];
 *
 */
#define X(tpnum, port, bit) {GPIO_DT_SPEC_GET(BP_NODE, tp ## tpnum ## _p ## port ## _ ## bit ## _gpios), tpnum, port, bit},
static const gpio_tp gpio_tp_array[NUM_GPIO_TPS] = {
	GPIO_DEFS
};
#undef X

static int gpios_init(void)
{
	/**
	 * The GPIO test points are configured by default as inputs with
	 * pulldowns. As an example of changing the configuration at
	 * runtime, rather than in the device tree at startup only, here
	 * we configure TP84, which is routed to Port 0 bit 3, as an
	 * output which is active.
	 * By setting TP84 to be an output, as shown below, you could
	 * hook up a new LED + resistor to TP84 and be able to turn it
	 * on and off.
	 */
#if 0
	const gpio_tp *my_new_led = &gpio_tp_array[TP84];
	int ret = gpio_pin_configure_dt(&my_new_led->dt, GPIO_OUTPUT_ACTIVE | GPIO_ACTIVE_HIGH);

	if (ret) {
	    return ret;
	}
#endif

#if 0
	// modify the handle_gpios() function below to also toggle the new LED

	const gpio_tp *my_new_led = &gpio_tp_array[TP84]; // <-- add this line

	for (;;) {
		gpios_log();
		k_msleep(1000);
		gpio_pin_toggle_dt(&my_new_led->dt); // <-- add this line
	}
#endif
	return 0;
}

static int gpios_log(void)
{
	/* enumerate all GPIOs and print their definitions as well as their currently read hardware value. */
	for (int i = 0; i < NUM_GPIO_TPS; i++) {
		LOG_DBG("TP%d P%d_%d = %u", gpio_tp_array[i].tpnum, gpio_tp_array[i].port, gpio_tp_array[i].bit, gpio_pin_get_dt(&gpio_tp_array[i].dt));
	}
	return 0;
}

#else

static int gpios_init(void)
{
	LOG_INF("No GPIOs defined.");
	return 0;
}

static int gpios_log(void)
{
	return 0;
}

#endif

static int handle_gpios(void *p1, void *p2, void *p3)
{
	int ret;

	k_thread_name_set(gpio_id, "gpio_thread");
	LOG_INF("Starting GPIO demo");

	/* Can we use the GPIOs? */
	ret = gpios_init();

	if (ret != 0) {
		LOG_ERR("GPIO device(s) is not ready: %d", ret);
		return -1;
	}

	for (;;) {
		gpios_log();
		k_msleep(GPIO_SLEEP_TIME_MS);
	}

	return 0;
}

K_THREAD_DEFINE(gpio_id, STACKSIZE, handle_gpios, NULL, NULL, NULL, PRIORITY_GPIO, 0, 0);
```

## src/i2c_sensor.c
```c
/**
 * i2c_sensor.c
 *
 * Original code came from zephyr/samples/sensor/bme280.
 *
 * Modified slightly to run as a thread and use logging.
 */
#include <stdio.h>
#include <zephyr/kernel.h>
#include <zephyr/sys/printk.h> 
#include <zephyr/sys/__assert.h>

#include <zephyr/device.h>
#include <zephyr/devicetree.h>
#include <zephyr/drivers/sensor.h>
#include <zephyr/drivers/sensor_data_types.h>
#include <zephyr/rtio/rtio.h>
#include <zephyr/logging/log.h>

LOG_MODULE_REGISTER(oresat_i2c_sensor_demo, LOG_LEVEL_DBG);

/* size of stack area used by each thread */
#define STACKSIZE 2048

/* scheduling priority used by each thread */
#define PRIORITY 7

/* 1000 msec = 1 sec */
#define BME_SLEEP_TIME_MS   5000

static const struct device *check_bme280_device(const struct device *bme_dev)
{
	if (bme_dev == NULL) {
		/* No such node, or the node does not have status "okay". */
		LOG_ERR("\nError: no device found.");
		return NULL;
	}

	if (!device_is_ready(bme_dev)) {
		LOG_ERR("\nError: Device \"%s\" is not ready; "
		       "check the driver initialization logs for errors.",
		       bme_dev->name);
		return NULL;
	}

	LOG_INF("Found device \"%s\", getting sensor data", bme_dev->name);
	return bme_dev;
}

/*
 * Get a device structure from a devicetree node with compatible
 * "bosch,bme280". (If there are multiple, just pick one.)
 */
SENSOR_DT_READ_IODEV(iodev, DT_COMPAT_GET_ANY_STATUS_OKAY(bosch_bme280),
		{SENSOR_CHAN_AMBIENT_TEMP, 0},
		{SENSOR_CHAN_HUMIDITY, 0},
		{SENSOR_CHAN_PRESS, 0});

RTIO_DEFINE(ctx, 1, 1);

static int handle_bme280(void)
{
	int ret;
	uint8_t buf[128];
	const struct device *const bme_dev = DEVICE_DT_GET_ANY(bosch_bme280);

	LOG_INF("Starting I2C sensor demo");

	/* Can we use the I2C sensor? */
	if (check_bme280_device(bme_dev) == NULL) {
		LOG_ERR("Could not find the BME280");
		return -1;
	}

	/* Thread loop */
	while (1) {
		ret = sensor_read(&iodev, &ctx, buf, 128);
		if (ret != 0) {
			LOG_ERR("%s: sensor_read() failed: %d", bme_dev->name, ret);
			break;
		}

		const struct sensor_decoder_api *decoder;

		ret = sensor_get_decoder(bme_dev, &decoder);
		if (ret != 0) {
			LOG_ERR("%s: sensor_get_decode() failed: %d", bme_dev->name, ret);
			break;
		}

		uint32_t temp_fit = 0;
		struct sensor_q31_data temp_data = {0};

		decoder->decode(buf, (struct sensor_chan_spec) {SENSOR_CHAN_AMBIENT_TEMP, 0},
						&temp_fit, 1, &temp_data);

		uint32_t press_fit = 0;
		struct sensor_q31_data press_data = {0};

		decoder->decode(buf, (struct sensor_chan_spec) {SENSOR_CHAN_PRESS, 0},
						&press_fit, 1, &press_data);

		uint32_t hum_fit = 0;
		struct sensor_q31_data hum_data = {0};

		decoder->decode(buf, (struct sensor_chan_spec) {SENSOR_CHAN_HUMIDITY, 0},
						&hum_fit, 1, &hum_data);

		printk("temp: %s%d.%d; press: %s%d.%d; humidity: %s%d.%d\n",
			PRIq_arg(temp_data.readings[0].temperature, 6, temp_data.shift),
			PRIq_arg(press_data.readings[0].pressure, 6, press_data.shift),
			PRIq_arg(hum_data.readings[0].humidity, 6, hum_data.shift));

		k_msleep(BME_SLEEP_TIME_MS);
	}
	return ret;
}

K_THREAD_DEFINE(bme280_id, STACKSIZE, handle_bme280, NULL, NULL, NULL, PRIORITY, 0, 0);
```
